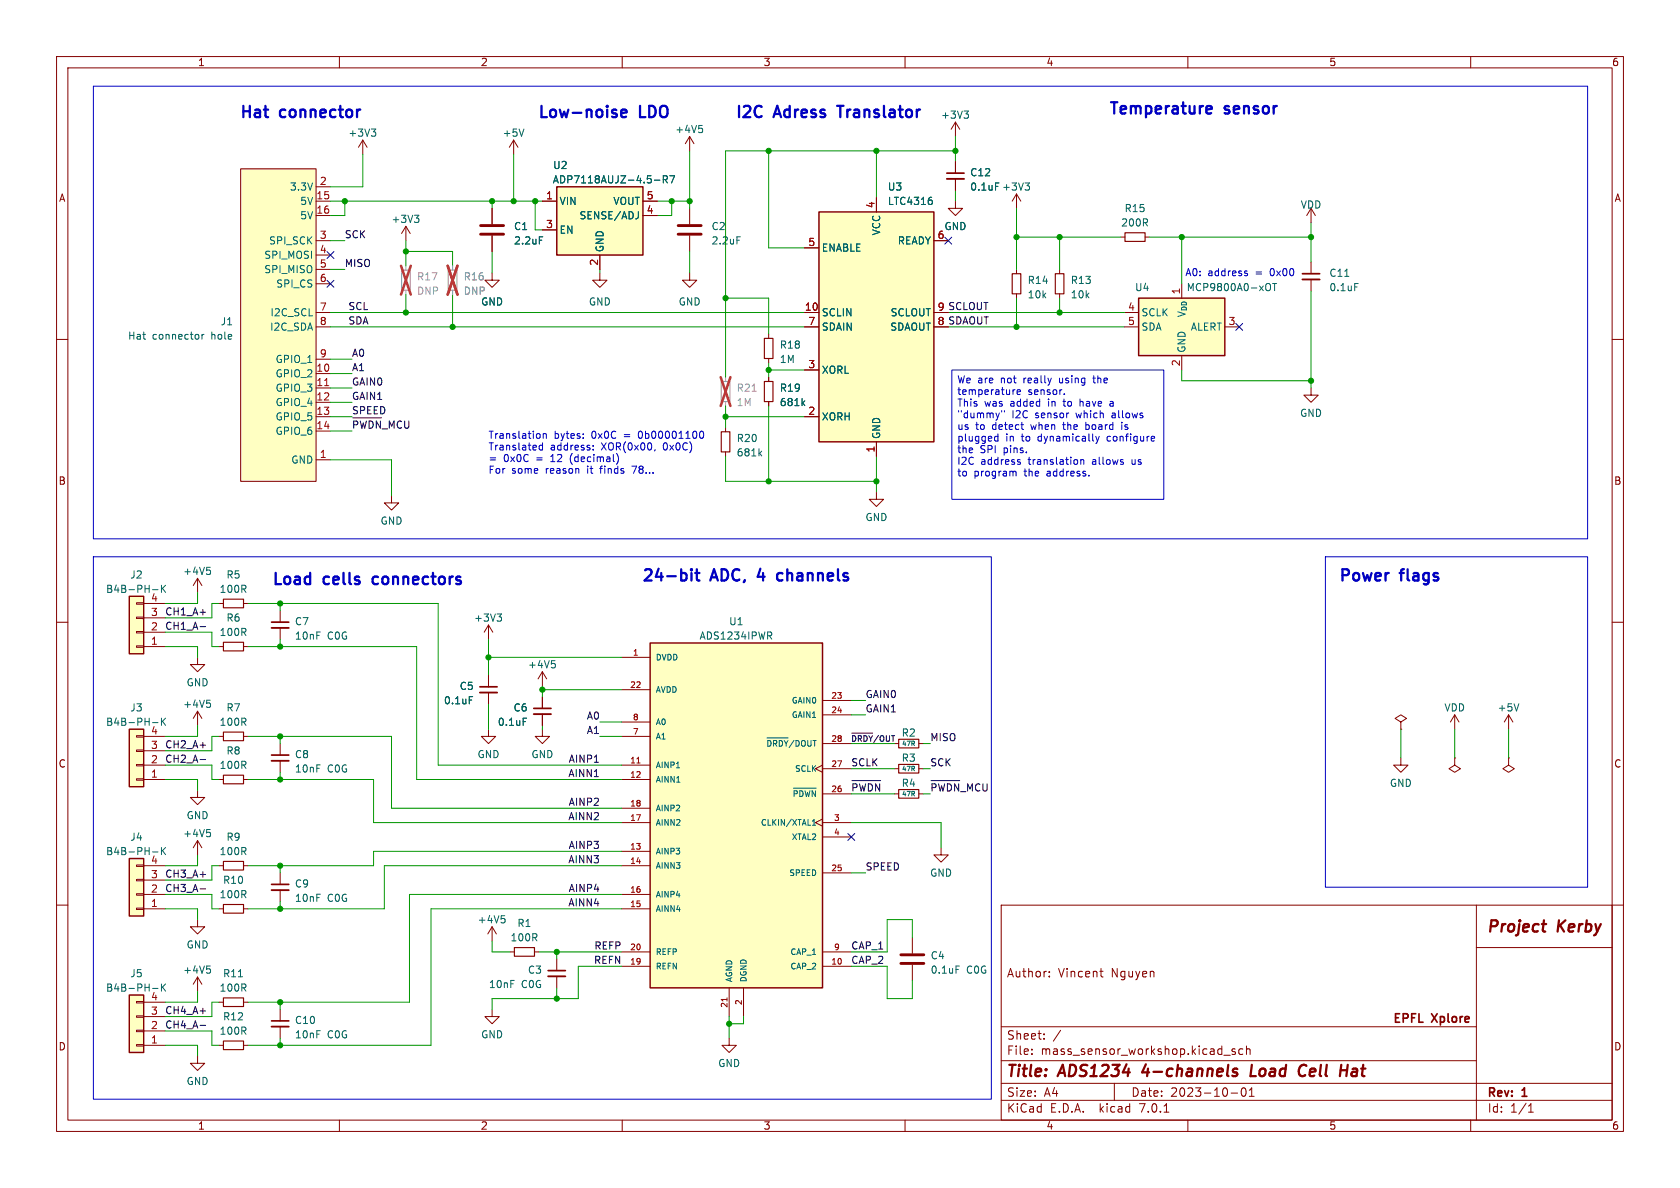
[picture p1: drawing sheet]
<svg xmlns="http://www.w3.org/2000/svg" width="297mm" height="210mm" viewBox="0 0 297 210" stroke-linecap="round" stroke-linejoin="round" font-family="sans-serif">
<defs><g id="words">
<g font-size="2.8" fill="#0000c2">
<text x="42.5" y="21">Hat</text>
<text x="49.7" y="21">connector</text>
<text x="95.2" y="21">Low-noise</text>
<text x="113.3" y="21">LDO</text>
<text x="130.2" y="21">I2C</text>
<text x="137.2" y="21">Adress</text>
<text x="149" y="21">Translator</text>
<text x="196.2" y="20.3">Temperature</text>
<text x="216.7" y="20.3">sensor</text>
<text x="48.3" y="103.5">Load</text>
<text x="57.4" y="103.5">cells</text>
<text x="66.7" y="103.5">connectors</text>
<text x="113.7" y="102.9">24-bit</text>
<text x="126" y="102.9">ADC,</text>
<text x="134.8" y="102.9">4</text>
<text x="138.8" y="102.9">channels</text>
<text x="236.9" y="102.9">Power</text>
<text x="247.8" y="102.9">flags</text>
</g>
<g font-size="2.8" fill="#840000">
<text x="262.7" y="165.3">Project</text>
<text x="275.2" y="165.3">Kerby</text>
<text x="178" y="190.8">Title:</text>
<text x="187.4" y="190.8">ADS1234</text>
<text x="202.7" y="190.8">4-channels</text>
<text x="222.4" y="190.8">Load</text>
<text x="231.5" y="190.8">Cell</text>
<text x="239.4" y="190.8">Hat</text>
</g>
<g font-size="2.1" fill="#840000">
<text x="178" y="172.9">Author:</text>
<text x="187.1" y="172.9">Vincent</text>
<text x="196.4" y="172.9">Nguyen</text>
<text x="178" y="183.9">Sheet:</text>
<text x="186.2" y="183.9">/</text>
<text x="245.9" y="181.1">EPFL</text>
<text x="252.9" y="181.1">Xplore</text>
<text x="178" y="186.6">File:</text>
<text x="184" y="186.6">mass_sensor_workshop.kicad_sch</text>
<text x="178" y="196.8">KiCad</text>
<text x="178" y="194">Size:</text>
<text x="184.6" y="194">A4</text>
<text x="185.7" y="196.8">E.D.A.</text>
<text x="194.4" y="196.8">kicad</text>
<text x="200" y="194">Date:</text>
<text x="201.5" y="196.8">7.0.1</text>
<text x="206.9" y="194">2023-10-01</text>
<text x="263" y="194.2">Rev:</text>
<text x="263" y="196.8">Id:</text>
<text x="267" y="196.8">1/1</text>
<text x="269.2" y="194.2">1</text>
</g>
<g font-size="1.8" fill="#840000">
<text x="35" y="11.8">1</text>
<text x="85" y="11.8">2</text>
<text x="135" y="11.8">3</text>
<text x="185" y="11.8">4</text>
<text x="235" y="11.8">5</text>
<text x="285" y="11.8">6</text>
<text x="10.4" y="35.8">A</text>
<text x="285.4" y="35.8">A</text>
<text x="10.3" y="85.8">B</text>
<text x="285.3" y="85.8">B</text>
<text x="10.3" y="135.8">C</text>
<text x="285.3" y="135.8">C</text>
<text x="10.3" y="185.8">D</text>
<text x="285.3" y="185.8">D</text>
<text x="35" y="199.8">1</text>
<text x="85" y="199.8">2</text>
<text x="135" y="199.8">3</text>
<text x="185" y="199.8">4</text>
<text x="235" y="199.8">5</text>
<text x="285" y="199.8">6</text>
</g>
<g font-size="1.8" fill="#006464">
<text x="119.3" y="23.7">+4V5</text>
<text x="166.3" y="21.1">+3V3</text>
<text x="61.5" y="24.3">+3V3</text>
<text x="88.8" y="24.3">+5V</text>
<text x="51.1" y="33.8">3.3V</text>
<text x="97.7" y="32.6">ADP7118AUJZ-4.5-R7</text>
<text x="97.7" y="30">U2</text>
<text x="156.9" y="33.8">U3</text>
<text x="171.5" y="31.3">C12</text>
<text x="171.5" y="33.9">0.1uF +3V3</text>
<text x="171.5" y="33.9">0.1uF</text>
<text x="52.9" y="36.4">5V</text>
<text x="52.9" y="38.9">5V</text>
<text x="69.2" y="39.6">+3V3</text>
<text x="90.8" y="40.8">C1</text>
<text x="98.9" y="36.4">VIN</text>
<text x="98.9" y="41.5">EN</text>
<text x="102.3" y="38.9">SENSE/ADJ</text>
<text x="108.3" y="36.4">VOUT</text>
<text x="125.7" y="40.8">C2</text>
<text x="155.8" y="41.7" transform="rotate(-90 155.8 41.7)">VCC</text>
<text x="156.9" y="36.4">LTC4316</text>
<text x="166.9" y="40.8">GND</text>
<text x="198.1" y="40.2">200R</text>
<text x="198.8" y="37.7">R15</text>
<text x="229.9" y="37">VDD</text>
<text x="46.6" y="45.9">SPI_MOSI</text>
<text x="47.4" y="43.4">SPI_SCK</text>
<text x="90.8" y="43.4">2.2uF</text>
<text x="106.9" y="44.6" transform="rotate(-90 106.9 44.6)">GND</text>
<text x="125.7" y="43.4">2.2uF</text>
<text x="145.3" y="44.6">ENABLE</text>
<text x="158.6" y="43.4">READY</text>
<text x="46.6" y="48.5">SPI_MISO</text>
<text x="48.7" y="51">SPI_CS</text>
<text x="181.6" y="50.4">R14</text>
<text x="181.6" y="52.9">10k</text>
<text x="189.2" y="50.4">R13</text>
<text x="189.2" y="52.9">10k</text>
<text x="200.6" y="51.6">U4</text>
<text x="209.7" y="51.6">MCP9800A0-xOT</text>
<text x="235" y="49.1">C11</text>
<text x="235" y="51.6">0.1uF</text>
<text x="39" y="57.7">J1</text>
<text x="47.6" y="58.6">I2C_SDA</text>
<text x="47.7" y="56.1">I2C_SCL</text>
<text x="85" y="54.2">GND</text>
<text x="104" y="54.2">GND</text>
<text x="119.9" y="54.2">GND</text>
<text x="145.3" y="56.1">SCLIN</text>
<text x="145.3" y="58.6">SDAIN</text>
<text x="157.3" y="58.6">SDAOUT</text>
<text x="157.3" y="56.1">SCLOUT</text>
<text x="201.8" y="56.1">SCLK</text>
<text x="201.8" y="58.6">SDA</text>
<text x="209.7" y="56.3" transform="rotate(-90 209.7 56.3)">V_{DD}</text>
<text x="210.4" y="58.6">ALERT</text>
<text x="22.6" y="60.2">Hat</text>
<text x="26.9" y="60.2">connector</text>
<text x="37.3" y="60.2">hole</text>
<text x="48.6" y="64.3">GPIO_1</text>
<text x="137.8" y="61.8">R18</text>
<text x="137.8" y="64.3">1M</text>
<text x="209.7" y="62.4" transform="rotate(-90 209.7 62.4)">GND</text>
<text x="48.6" y="66.9">GPIO_2</text>
<text x="48.6" y="69.4">GPIO_3</text>
<text x="48.6" y="71.9">GPIO_4</text>
<text x="137.8" y="69.4">R19</text>
<text x="137.8" y="71.9">681k</text>
<text x="145.3" y="66.2">XORL</text>
<text x="48.6" y="74.5">GPIO_5</text>
<text x="48.6" y="77">GPIO_6</text>
<text x="145.3" y="74.5">XORH</text>
<text x="155.8" y="77.6" transform="rotate(-90 155.8 77.6)">GND</text>
<text x="229.8" y="73.9">GND</text>
<text x="51.4" y="82.1">GND</text>
<text x="130.2" y="78.3">R20</text>
<text x="130.2" y="80.8">681k</text>
<text x="67.2" y="92.9">GND</text>
<text x="152.9" y="92.3">GND</text>
<text x="32.3" y="101.8">+4V5</text>
<text x="18.7" y="105">B4B-PH-K</text>
<text x="23" y="102.4">J2</text>
<text x="38.8" y="105">100R</text>
<text x="40" y="102.4">R5</text>
<text x="38.8" y="112.6">100R</text>
<text x="40" y="110">R6</text>
<text x="52.1" y="110.7">C7</text>
<text x="52.1" y="113.2">10nF</text>
<text x="57.8" y="113.2">C0G</text>
<text x="83.8" y="110">+3V3</text>
<text x="123.6" y="113.2">ADS1234IPWR</text>
<text x="128.8" y="110.7">U1</text>
<text x="93.3" y="118.3">+4V5</text>
<text x="23" y="125.9">J3</text>
<text x="32.3" y="125.3">+4V5</text>
<text x="32.9" y="121.5">GND</text>
<text x="40" y="125.9">R7</text>
<text x="78.4" y="124.7">0.1uF</text>
<text x="81.2" y="122.1">C5</text>
<text x="90.7" y="125.9">C6</text>
<text x="255.3" y="125.9">VDD</text>
<text x="264.7" y="125.9">+5V</text>
<text x="18.7" y="128.5">B4B-PH-K</text>
<text x="38.8" y="128.5">100R</text>
<text x="87.9" y="128.5">0.1uF</text>
<text x="159.4" y="130.4">R2</text>
<text x="38.8" y="136.1">100R</text>
<text x="40" y="133.5">R8</text>
<text x="52.1" y="134.2">C8</text>
<text x="52.1" y="136.7">10nF</text>
<text x="57.8" y="136.7">C0G</text>
<text x="84.4" y="134.2">GND</text>
<text x="93.9" y="134.2">GND</text>
<text x="159.4" y="134.8">R3</text>
<text x="159.4" y="139.3">R4</text>
<text x="245.7" y="139.3">GND</text>
<text x="23" y="148.8">J4</text>
<text x="32.3" y="148.1">+4V5</text>
<text x="32.9" y="145">GND</text>
<text x="40" y="148.8">R9</text>
<text x="18.7" y="151.3">B4B-PH-K</text>
<text x="38.8" y="151.3">100R</text>
<text x="164.4" y="155.1">GND</text>
<text x="38.8" y="158.9">100R</text>
<text x="39.4" y="156.4">R10</text>
<text x="52.1" y="157">C9</text>
<text x="52.1" y="159.6">10nF</text>
<text x="57.8" y="159.6">C0G</text>
<text x="32.9" y="167.8">GND</text>
<text x="84.4" y="163.4">+4V5</text>
<text x="90.2" y="166.6">100R</text>
<text x="91.4" y="164">R1</text>
<text x="23" y="172.9">J5</text>
<text x="32.3" y="172.3">+4V5</text>
<text x="39.4" y="172.9">R11</text>
<text x="93.3" y="172.3">C3</text>
<text x="164.5" y="169.7">C4</text>
<text x="164.5" y="172.3">0.1uF</text>
<text x="170.8" y="172.3">C0G</text>
<text x="18.7" y="175.5">B4B-PH-K</text>
<text x="38.8" y="175.5">100R</text>
<text x="86.4" y="174.8">10nF</text>
<text x="92.1" y="174.8">C0G</text>
<text x="38.8" y="183.1">100R</text>
<text x="39.4" y="180.5">R12</text>
<text x="52.1" y="181.2">C10</text>
<text x="52.1" y="183.7">10nF</text>
<text x="57.8" y="183.7">C0G</text>
<text x="85" y="183.7">GND</text>
<text x="32.9" y="192">GND</text>
<text x="126.9" y="188.8">GND</text>
</g>
<g font-size="1.8" fill="#a90000">
<text x="55.9" y="35.3">15</text>
<text x="56.5" y="32.8">2</text>
<text x="96.5" y="35.3">1</text>
<text x="114.3" y="35.3">5</text>
<text x="55.9" y="37.8">16</text>
<text x="96.5" y="40.4">3</text>
<text x="114.3" y="37.8">4</text>
<text x="154.7" y="36.9" transform="rotate(-90 154.7 36.9)">4</text>
<text x="56.5" y="42.3">3</text>
<text x="56.5" y="44.8">4</text>
<text x="56.5" y="47.4">5</text>
<text x="105.8" y="47" transform="rotate(-90 105.8 47)">2</text>
<text x="142.8" y="43.6">5</text>
<text x="165.7" y="42.3">6</text>
<text x="56.5" y="49.9">6</text>
<text x="208.7" y="52.1" transform="rotate(-90 208.7 52.1)">1</text>
<text x="56.5" y="55">7</text>
<text x="56.5" y="57.5">8</text>
<text x="142.2" y="55">10</text>
<text x="142.8" y="57.5">7</text>
<text x="165.7" y="57.5">8</text>
<text x="165.7" y="55">9</text>
<text x="199.4" y="55">4</text>
<text x="199.4" y="57.5">5</text>
<text x="217.1" y="57.5">3</text>
<text x="55.9" y="65.8">10</text>
<text x="56.5" y="63.2">9</text>
<text x="142.8" y="65.2">3</text>
<text x="208.7" y="64.8" transform="rotate(-90 208.7 64.8)">2</text>
<text x="55.9" y="68.3">11</text>
<text x="55.9" y="70.9">12</text>
<text x="55.9" y="73.4">13</text>
<text x="55.9" y="75.9">14</text>
<text x="142.8" y="73.4">2</text>
<text x="56.5" y="81">1</text>
<text x="154.7" y="80" transform="rotate(-90 154.7 80)">1</text>
<text x="26.6" y="106.4">4</text>
<text x="26.6" y="111.5">2</text>
<text x="26.6" y="109">3</text>
<text x="26.6" y="114">1</text>
<text x="26.6" y="129.9">4</text>
<text x="26.6" y="137.5">1</text>
<text x="26.6" y="135">2</text>
<text x="26.6" y="132.5">3</text>
<text x="26.6" y="155.3">3</text>
<text x="26.6" y="152.8">4</text>
<text x="26.6" y="160.4">1</text>
<text x="26.6" y="157.9">2</text>
<text x="26.6" y="179.5">3</text>
<text x="26.6" y="176.9">4</text>
<text x="26.6" y="184.5">1</text>
<text x="26.6" y="182">2</text>
</g>
<g font-size="1.8" fill="#0f0f0f">
<text x="61" y="42.2">SCK</text>
<text x="61" y="47.3">MISO</text>
<text x="61.6" y="54.9">SCL</text>
<text x="61.6" y="57.4">SDA</text>
<text x="165.7" y="57.5">8 SDAOUT</text>
<text x="165.7" y="55">9 SCLOUT</text>
<text x="62.2" y="65.7">A1</text>
<text x="62.2" y="63.2">A0</text>
<text x="62.2" y="70.8">GAIN1</text>
<text x="62.2" y="68.2">GAIN0</text>
<text x="62.2" y="73.3">SPEED</text>
<text x="62.2" y="75.9">~{PWDN}_MCU</text>
<text x="29.2" y="111.4">CH1_A-</text>
<text x="29.2" y="108.9">CH1_A+</text>
<text x="153" y="123.5">GAIN0</text>
<text x="103.6" y="127.3">A0</text>
<text x="103.6" y="129.8">A1</text>
<text x="153" y="126">GAIN1</text>
<text x="164.5" y="131.1">MISO</text>
<text x="29.2" y="132.4">CH2_A+</text>
<text x="29.2" y="134.9">CH2_A-</text>
<text x="100.4" y="137.4">AINN1</text>
<text x="100.4" y="134.9">AINP1</text>
<text x="150.5" y="135.5">SCLK</text>
<text x="164.5" y="135.5">SCK</text>
<text x="100.4" y="142.5">AINP2</text>
<text x="150.5" y="140">~{PWDN}</text>
<text x="164.5" y="140">~{PWDN}_MCU</text>
<text x="100.4" y="145.1">AINN2</text>
<text x="29.2" y="155.2">CH3_A+</text>
<text x="100.4" y="152.7">AINN3</text>
<text x="100.4" y="150.1">AINP3</text>
<text x="153" y="154">SPEED</text>
<text x="29.2" y="157.8">CH3_A-</text>
<text x="100.4" y="160.3">AINN4</text>
<text x="100.4" y="157.8">AINP4</text>
<text x="105" y="167.9">REFP</text>
<text x="150.5" y="167.9">CAP_1</text>
<text x="104.9" y="170.5">REFN</text>
<text x="150.5" y="170.5">CAP_2</text>
<text x="29.2" y="179.4">CH4_A+</text>
<text x="29.2" y="181.9">CH4_A-</text>
</g>
<g font-size="1.8" fill="#989898">
<text x="73.7" y="49.7">R17</text>
<text x="73.7" y="52.3">DNP</text>
<text x="81.9" y="49.7">R16</text>
<text x="81.9" y="52.3">DNP</text>
<text x="130.2" y="69.4">R21</text>
<text x="130.2" y="71.9">1M</text>
</g>
<g font-size="1.8" fill="#0000c2">
<text x="209.5" y="48.9">A0:</text>
<text x="213.5" y="48.9">address</text>
<text x="222" y="48.9">=</text>
<text x="224.7" y="48.9">0x00</text>
<text x="169.2" y="68">We are</text>
<text x="169.2" y="70.1">temperature</text>
<text x="177" y="68">not</text>
<text x="181.1" y="68">really</text>
<text x="181.8" y="70.1">sensor.</text>
<text x="187.5" y="68">using</text>
<text x="193.7" y="68">the</text>
<text x="86.4" y="77.6">Translation</text>
<text x="98" y="77.6">bytes:</text>
<text x="104.6" y="77.6">0x0C</text>
<text x="110.4" y="77.6">=</text>
<text x="113.1" y="77.6">0b00001100</text>
<text x="169.2" y="72.1">This</text>
<text x="169.2" y="74.2">&quot;dummy&quot;</text>
<text x="169.2" y="76.2">us</text>
<text x="172.5" y="76.2">to</text>
<text x="174.1" y="72.1">was</text>
<text x="175.5" y="76.2">detect</text>
<text x="178.7" y="72.1">added</text>
<text x="178.9" y="74.2">I2C</text>
<text x="182.4" y="76.2">when</text>
<text x="183.1" y="74.2">sensor</text>
<text x="185.5" y="72.1">in</text>
<text x="188.2" y="76.2">the</text>
<text x="188.3" y="72.1">to</text>
<text x="190.4" y="74.2">which</text>
<text x="191.3" y="72.1">have</text>
<text x="192.3" y="76.2">board</text>
<text x="196.7" y="72.1">a</text>
<text x="196.8" y="74.2">allows</text>
<text x="198.8" y="76.2">is</text>
<text x="86.4" y="79.7">Translated</text>
<text x="86.4" y="81.8">=</text>
<text x="86.4" y="83.8">For</text>
<text x="89" y="81.8">0x0C</text>
<text x="90.5" y="83.8">some</text>
<text x="94.8" y="81.8">=</text>
<text x="96.5" y="83.8">reason</text>
<text x="97.3" y="79.7">address:</text>
<text x="97.5" y="81.8">12</text>
<text x="101" y="81.8">(decimal)</text>
<text x="104" y="83.8">it</text>
<text x="106.4" y="79.7">XOR(0x00,</text>
<text x="106.4" y="83.8">finds</text>
<text x="112.2" y="83.8">78...</text>
<text x="117.4" y="79.7">0x0C)</text>
<text x="169.2" y="78.3">plugged</text>
<text x="169.2" y="80.4">the</text>
<text x="169.2" y="82.4">I2C</text>
<text x="173.3" y="80.4">SPI</text>
<text x="173.4" y="82.4">address</text>
<text x="177.5" y="80.4">pins.</text>
<text x="177.8" y="78.3">in</text>
<text x="180.7" y="78.3">to</text>
<text x="181.9" y="82.4">translation</text>
<text x="183.6" y="78.3">dynamically</text>
<text x="193.3" y="82.4">allows</text>
<text x="196" y="78.3">configure</text>
<text x="200.3" y="82.4">us</text>
<text x="169.2" y="84.5">to</text>
<text x="172.2" y="84.5">program</text>
<text x="181.2" y="84.5">the</text>
<text x="185.2" y="84.5">address.</text>
</g>
<g font-size="1.4" fill="#a90000">
<text x="111.8" y="116">1</text>
<text x="111.3" y="121.7">22</text>
<text x="146.9" y="123.6">23</text>
<text x="111.8" y="129.9">7</text>
<text x="111.8" y="127.4">8</text>
<text x="146.9" y="126.1">24</text>
<text x="146.9" y="131.2">28</text>
<text x="111.3" y="135">11</text>
<text x="111.3" y="137.5">12</text>
<text x="146.9" y="135.6">27</text>
<text x="111.3" y="142.6">18</text>
<text x="146.9" y="140.1">26</text>
<text x="111.3" y="145.2">17</text>
<text x="147.4" y="145.2">3</text>
<text x="147.4" y="147.7">4</text>
<text x="111.3" y="150.2">13</text>
<text x="111.3" y="152.8">14</text>
<text x="146.9" y="154.1">25</text>
<text x="111.3" y="160.4">15</text>
<text x="111.3" y="157.9">16</text>
<text x="111.3" y="170.6">19</text>
<text x="111.3" y="168">20</text>
<text x="146.9" y="170.6">10</text>
<text x="147.4" y="168">9</text>
<text x="128.7" y="178.2" transform="rotate(-90 128.7 178.2)">21</text>
<text x="131.2" y="177.7" transform="rotate(-90 131.2 177.7)">2</text>
</g>
<g font-size="1.4" fill="#006464">
<text x="116" y="116.9">DVDD</text>
<text x="116" y="122.6">AVDD</text>
<text x="139.8" y="124.5">GAIN0</text>
<text x="116" y="130.9">A1</text>
<text x="116" y="128.3">A0</text>
<text x="139.8" y="127.1">GAIN1</text>
<text x="116" y="136">AINP1</text>
<text x="135.3" y="132.6">~{DRDY}/DOUT</text>
<text x="140.4" y="136.6">SCLK</text>
<text x="116" y="138.5">AINN1</text>
<text x="116" y="143.6">AINP2</text>
<text x="140" y="141.5">~{PDWN}</text>
<text x="116" y="146.1">AINN2</text>
<text x="134.4" y="146.1">CLKIN/XTAL1</text>
<text x="139.8" y="148.7">XTAL2</text>
<text x="116" y="151.2">AINP3</text>
<text x="116" y="153.7">AINN3</text>
<text x="139.4" y="155">SPEED</text>
<text x="116" y="161.4">AINN4</text>
<text x="116" y="158.8">AINP4</text>
<text x="116" y="171.5">REFN</text>
<text x="116" y="169">REFP</text>
<text x="129.6" y="173.6" transform="rotate(-90 129.6 173.6)">AGND</text>
<text x="132.1" y="173.6" transform="rotate(-90 132.1 173.6)">DGND</text>
<text x="139.6" y="171.5">CAP_2</text>
<text x="139.6" y="169">CAP_1</text>
</g>
<text font-size="1.4" fill="#0f0f0f" x="150.5" y="131.2">~{DRDY}/OUT</text>
<g font-size="1.1" fill="#006464">
<text x="159.4" y="132">47R</text>
<text x="159.4" y="136.5">47R</text>
<text x="159.4" y="140.9">47R</text>
</g>
</g></defs>
<g fill="none" stroke="#840000" stroke-width=".18">
<path d="M10 10h277v190h-277zM12 12h273v186h-273zM60 10v2M110 10v2M160 10v2M210 10v2M260 10v2M42.5 29.8h13.4v55.3h-13.4zM55.9 35.6h2.5M55.9 38.1h2.5M55.9 33h2.5M64.1 24.8l-.7 1.2"/>
<path d="M64.1 24.8v2.5M64.1 24.8l.8 1.2M87 36.8v2.8M90.8 24.8l-.8 1.2M90.8 24.8v2.5M90.8 24.8l.8 1.2M95.9 35.6h2.5M113.7 35.6h2.5M113.7 38.1h2.5M121.9 24.1l-.7 1.3M121.9 24.1v2.6M121.9 36.8v2.8"/>
<path d="M121.9 24.1l.8 1.3M154.9 34.9v2.6M168.9 35.6v1.2h1.3l-1.3 1.3-1.3-1.3h1.3M168.9 21.6l-.8 1.3M168.9 21.6v2.5M168.9 28.6v2M168.9 31.6v2.1M168.9 21.6l.8 1.3M179.7 34.3v2.5M179.7 34.3l-.8 1.3M179.7 34.3l.8 1.3M231.8 36.8v2.6"/>
<path d="M231.8 36.8l-.8 1.3M231.8 36.8l.7 1.3M10 60h2M55.9 42.5h2.5M55.9 45.1h2.5M55.9 47.6h2.5M55.9 50.2h2.5M55.9 55.2h2.5M55.9 57.8h2.5M71.8 40l-.8 1.3M71.8 40v2.5M71.8 40l.7 1.3"/>
<path d="M87 48.3v1.2h1.3l-1.3 1.3-1.3-1.3h1.3M87 41.7v2.8M95.9 40.6h2.5M106 48.3v1.2h1.3l-1.3 1.3-1.2-1.3h1.2M106 45.1v2.5M121.9 48.3v1.2h1.3l-1.3 1.3-1.3-1.3h1.3M121.9 41.7v2.8M135.9 59.1v.7M142.2 55.2h2.6M142.2 57.8h2.6M142.2 43.8h2.6M165.1 42.5h2.5"/>
<path d="M165.1 55.2h2.5M165.1 57.8h2.5M179.7 47.6v.8M179.7 51.9v.8M187.3 47.6v.8M187.3 51.9v.8M198.1 41.9h.8M198.8 55.2h2.5M198.8 57.8h2.5M202.4 41.9h.8M216.5 57.8h2.6M231.8 46.4v2"/>
<path d="M231.8 49.4v2M285 60h2M55.9 66h2.5M55.9 68.6h2.5M55.9 71.1h2.5M55.9 73.7h2.5M55.9 76.2h2.5M55.9 63.5h2.5M128.3 75.6v.7M128.3 79.9v.7M135.9 63.4v.7M135.9 66.7v.7"/>
<path d="M135.9 71v.8M142.2 73.7h2.6M142.2 65.4h2.6M154.9 78.1v2.5M208.9 62.9v2.5M231.8 68.6v1.3h1.2l-1.2 1.2-1.3-1.2h1.3M55.9 81.3h2.5M69.2 87.6v1.3h1.3l-1.3 1.3-1.3-1.3h1.3M154.9 87v1.3h1.3l-1.3 1.2-1.2-1.2h1.2M10 110h2M24.1 106.6h1.3v.2h-1.3zM24.1 109.1h1.3v.2h-1.3z"/>
<path d="M24.1 111.6h1.3v.3h-1.3zM24.1 114.2h1.3v.2h-1.3zM25.4 106.7h3.8M25.4 114.3h3.8M25.4 111.8h3.8M25.4 109.2h3.8M34.9 116.2v1.3h1.3l-1.3 1.2-1.2-1.2h1.2M34.9 102.2v2.6M34.9 102.2l-.7 1.3M34.9 102.2l.8 1.3M38.7 106.7h.8M38.7 114.3h.8"/>
<path d="M43.1 106.7h.7M43.1 114.3h.7M49.5 108v2M49.5 111v2M86.4 110.5v2.5M86.4 119.4v2M86.4 110.5l-.8 1.3M86.4 110.5l.7 1.3M95.9 118.7v2.6M95.9 118.7l-.8 1.3M95.9 118.7l.7 1.3M109.9 116.2h5"/>
<path d="M285 110h2M24.1 130h1.3v.3h-1.3zM24.1 132.6h1.3v.2h-1.3zM24.1 135.1h1.3v.3h-1.3zM24.1 137.7h1.3v.2h-1.3zM25.4 137.8h3.8M25.4 135.3h3.8M25.4 132.7h3.8M25.4 130.2h3.8M34.9 139.7v1.3h1.3l-1.3 1.2-1.2-1.2h1.2M34.9 125.7v2.6M34.9 125.7l-.7 1.3"/>
<path d="M34.9 125.7l.8 1.3M38.7 137.8h.8M38.7 130.2h.8M43.1 137.8h.7M43.1 130.2h.7M49.5 131.4v2.1M49.5 134.5v2M86.4 128.9v1.3h1.2l-1.2 1.2-1.3-1.2h1.3M86.4 122.4v2.1M95.9 128.9v1.3h1.3l-1.3 1.2-1.3-1.2h1.3M95.9 123.2v2M95.9 126.2v2.1"/>
<path d="M109.9 137.8h5M109.9 135.3h5M109.9 130.2h5M109.9 121.9h5M109.9 127.6h5M145.4 135.3l-1.3 .6 1.3 .6M145.4 131.4h5.1M145.4 135.9h5.1M145.4 123.8h5.1M145.4 126.4h5.1M158.1 135.9h.8M162.4 131.4h.8"/>
<path d="M162.4 135.9h.8M247.6 127.6l1.1-.6-1.1-.6-1 .6 1 .6v1.3M247.6 128.9h.1M247.6 134v1.3h1.3l-1.3 1.2-1.2-1.2h1.2M257.2 134v1.3l1 .6-1 .6-1-.6 1-.6M257.2 134h.1M257.2 126.4l-.8 1.2M257.2 126.4v2.5M257.2 126.4l.7 1.2M266.7 134v1.3l1 .6-1 .6-1-.6 1-.6M266.7 134h.1M266.7 126.4l-.8 1.2"/>
<path d="M266.7 126.4v2.5M266.7 126.4l.8 1.2M10 160h2M24.1 152.9h1.3v.3h-1.3zM24.1 155.4h1.3v.3h-1.3zM24.1 158h1.3v.2h-1.3zM25.4 158.1h3.8M25.4 155.6h3.8M25.4 153h3.8M34.9 148.6v2.5M34.9 148.6l-.7 1.3M34.9 148.6l.8 1.3"/>
<path d="M38.7 153h.8M43.1 153h.7M49.5 154.3v2M49.5 157.4v2M109.9 158.1h5M109.9 153h5M109.9 150.5h5M109.9 145.4h5M109.9 142.9h5M145.4 144.8l-1.3 .6 1.3 .7M145.4 140.3h5.1M145.4 145.4h5.1"/>
<path d="M145.4 154.3h5.1M145.4 148h5.1M158.1 140.3h.8M162.4 140.3h.8M166.4 149.9v1.2h1.2l-1.2 1.3-1.3-1.3h1.3M285 160h2M24.1 160.5h1.3v.3h-1.3zM24.1 177h1.3v.3h-1.3zM24.1 179.6h1.3v.2h-1.3zM25.4 177.2h3.8M25.4 160.7h3.8M25.4 179.7h3.8"/>
<path d="M34.9 162.6v1.2h1.3l-1.3 1.3-1.2-1.3h1.2M34.9 172.7l-.7 1.3M34.9 172.7v2.6M34.9 172.7l.8 1.3M38.7 177.2h.8M38.7 160.7h.8M43.1 177.2h.7M43.1 160.7h.7M49.5 178.4v2.1M87 178.4v1.3h1.3l-1.3 1.3-1.3-1.3h1.3M87 163.8l-.8 1.3M87 163.8v2.6"/>
<path d="M87 163.8l.8 1.3M90.2 168.3h.7M94.5 168.3h.7M98.4 169.5v2.1M98.4 172.6v2M109.9 160.7h5M109.9 168.3h5M109.9 170.8h5M128.9 174.6v5.1M131.4 174.6v5.1M145.4 168.3h5.1M145.4 170.8h5.1"/>
<path d="M161.3 165.7v2.8M161.3 170.6v2.8M177 160h108v38h-108zM185.5 172.6v.1M185.5 171.8v.1M194.4 171.7h.6M194.7 172.6l.3 .1M261 160v38M261 167.5h24M24.1 182.1h1.3v.3h-1.3zM24.1 184.7h1.3v.2h-1.3zM25.4 184.8h3.8"/>
<path d="M25.4 182.2h3.8M34.9 186.7v1.3h1.3l-1.3 1.2-1.2-1.2h1.2M38.7 184.8h.8M43.1 184.8h.7M49.5 181.5v2M60 198v2M110 198v2M128.9 183.5v1.3h1.3l-1.3 1.3-1.3-1.3h1.3M160 198v2M177 194.5h108M177 191.5h108M177 187.5h84"/>
<path d="M177 181.5h84M182.4 186.3v.1M182.4 185.5v.1M184.6 183.6v.1M184.6 182.8v.1M197 191.5v3M205.8 196.6h.8M210 198v2M216.4 186.5h1.1M217.6 193.2h1.2M218.4 185.5l-.4-.1-.2 .2 .1 .2 .5 .2v.3h-.6M219.6 192.4l.2-.1a.81 .81 0 0 1 .6 .6 .81 .81 0 0 1-.3 .8l-.2 .1a.81 .81 0 0 1-.6-.6 .81 .81 0 0 1 .3-.8z"/>
<path d="M219.7 185.5l-.4-.1-.3 .3v.4l.1 .2h.6M220.4 185.5l.2-.1 .3 .1 .1 .9M220.4 184.9v1.5M220.9 193.8h.8M220.9 192.7l.4-.4v1.5M260 198v2M270.2 196.6h.9M270.2 195.5l.4-.4v1.5"/>
</g>
<path d="M272.6 163.3h.7M218.1 189l.2-.1 .5 .1M218.2 189.6l.5 .1v.2l-.3 .3h-.4M221.3 188.2l-.2 2h.9M230.1 188.3l.3-.1 .5 .1M230.8 190l-.6 .2M237 189.2h1.1M238.3 188.2l-.3 2" fill="none" stroke="#840000" stroke-width=".4"/>
<g fill="none" stroke="#840000" stroke-width=".2">
<path d="M135.1 59.8h1.6v3.6h-1.6zM178.9 48.4h1.6v3.5h-1.6zM186.6 48.4h1.5v3.5h-1.5zM198.9 41.1h3.5v1.6h-3.5zM127.5 76.3h1.5v3.6h-1.5zM135.1 67.4h1.6v3.6h-1.6zM39.5 105.9h3.6v1.5h-3.6zM39.5 113.5h3.6v1.6h-3.6zM39.5 129.4h3.6v1.5h-3.6zM39.5 137h3.6v1.6h-3.6zM158.9 130.7h3.5v1.5h-3.5zM158.9 139.6h3.5v1.5h-3.5z"/>
<path d="M158.9 135.1h3.5v1.6h-3.5zM39.5 159.9h3.6v1.5h-3.6zM39.5 152.3h3.6v1.5h-3.6zM39.5 176.4h3.6v1.5h-3.6zM90.9 167.5h3.6v1.5h-3.6zM39.5 184h3.6v1.5h-3.6z"/>
</g>
<g fill="#ffffc2" stroke="#ffffc2" stroke-width=".18">
<path d="M42.5 29.8h13.4v55.3h-13.4z"/>
<path d="M144.8 37.5h20.3v40.6h-20.3z"/>
<path d="M22.9 151.8h2.5v10.1h-2.5z"/>
<path d="M22.9 128.9h2.5v10.2h-2.5z"/>
<path d="M22.9 105.4h2.5v10.2h-2.5z"/>
<path d="M201.3 52.7h15.2v10.2h-15.2z"/>
<path d="M22.9 175.9h2.5v10.2h-2.5z"/>
<path d="M114.9 113.7h30.5v60.9h-30.5z"/>
<path d="M98.4 33h15.3v12.1h-15.3z"/>
</g>
<path d="M57.4 68.2h.7M112.6 134.9h.6M128.5 176.4v.6" fill="none" stroke="#a90000" stroke-width=".18"/>
<g fill="none" stroke="#006464" stroke-width=".18">
<path d="M170.4 19.6h.8l-.4 .5M65.6 22.8h.8l-.4 .5M66.2 23.3l.2 .2v.3l-.2 .3M73.3 38.1h.8l-.5 .4M73.8 38.5l.3 .3v.3l-.3 .2M92.6 22.8l-.4 1.3M112.9 37.4v.9l-.4 .4M115.7 31.9h1M117.3 31.7h.6l.1-.2-.1-.3-.6-.1v1.2M117.6 31.7l.4 .6M118.4 31.1h.9l-.6 1.2M123.6 22.2h.6"/>
<path d="M124 22.7l.2 .2v.3l-.2 .2M164.7 35.4l.1 .2-.1 .5M171 20.1l.2 .3v.3l-.2 .2M181.2 32.3h.8l-.4 .5M181.8 32.8l.2 .3v.3l-.2 .2M35.7 59.1v.9M36.1 59.1l-.4 .3M95.4 41.9h.6M130.3 41.9h.6M224.1 50.1a.43 .43 0 0 1 .5 .4v.5a.43 .43 0 0 1-.5 .4M225 50.1h.7M225.3 50.1v1.3"/>
<path d="M239.5 50.1h.6M134.7 79.8l-.5 .4M141.9 71.2l.4 .5M142.3 70.9l-.5 .4M134.3 80.1l.4 .5M27 104.2h.9M28.5 103.5v1.2M28.7 104l.6 .7M29.3 103.5l-.8 .7M36.6 100.3h.6M37 100.8l.2 .2v.3l-.2 .3M87.9 108.5h.8l-.5 .5"/>
<path d="M88.4 109l.3 .3v.3l-.3 .2M97.5 116.8h.6M97.9 117.3l.3 .2v.3l-.3 .3M136 112.4l.4 .6M136.3 111.8l.1 .2-.1 .3M27 127.7h.9M28.5 127v1.2M28.7 127.5l.6 .7M29.3 127l-.8 .7M36.6 123.8h.6M37 124.3l.2 .2v.3l-.2 .2M83 123.1h.6"/>
<path d="M92.5 127h.6M135.6 130.4h3.7M136.3 131.1l-.2-.2h-.4v1M137.3 131.2l-.1-.3h-.4v1M138.3 131.1l-.1-.2h-.4v1M138.6 130.9l.4 .5 .3-.5M140.2 139.3h4.1M140.4 130.9l-.9 1.3M141.3 131.1l-.2-.2h-.4v1M141.7 131.2a.34 .34 0 0 1 .3-.3 .34 .34 0 0 1 .4 .3M142.3 139.8l.3 1M142.8 130.9v.8"/>
<path d="M143.2 139.8l-.3 1M143.4 130.9v.8M143.7 130.9h.6M144 130.9v1M144.2 139.8v1l-.6-1v1M268.5 124.4l-.4 1.3M27 150.6h.9M28.5 149.8v1.3M28.7 150.4l.6 .7M29.3 149.8l-.8 .7M36.6 146.6h.6M37 147.1l.2 .3v.3l-.2 .2"/>
<path d="M141 140.1l-.1-.3h-.5v1M141.9 140l-.1-.2h-.4v1M143.6 145.9h.6M143.6 145.2l.3-.3v1M27 174.7h.9M28.5 173.9v1.3M28.7 174.5l.6 .7M29.3 173.9l-.8 .8M36.6 170.8h.6M37 171.3l.2 .2v.3l-.2 .2M88.6 161.9h.6M89.1 162.4l.2 .2v.3l-.2 .2"/>
<path d="M169 170.8h.6"/>
</g>
<path d="M85 39.9h4M119.9 39.9h4.1M85 41.4h4M119.9 41.4h4.1M159.3 170.3h4M159.3 168.8h4" fill="none" stroke="#840000" stroke-width=".51"/>
<path d="M167.4 31.6h3M230.3 49.4h3M48 111h3.1M48 134.5h3.1M84.8 122.4h3.1M94.4 126.2h3M48 157.4h3.1M96.9 172.6h3M48 181.5h3.1" fill="none" stroke="#840000" stroke-width=".33"/>
<path d="M167.4 30.6h3M230.3 48.4h3M48 110h3.1M48 133.5h3.1M84.8 121.4h3.1M94.4 125.2h3M48 156.3h3.1M96.9 171.6h3M48 180.5h3.1" fill="none" stroke="#840000" stroke-width=".3"/>
<path d="M98.4 33h15.3v12.1h-15.3zM144.8 37.5h20.3v40.6h-20.3zM201.3 52.7h15.2v10.2h-15.2zM22.9 105.4h2.5v10.2h-2.5zM114.9 113.7h30.5v60.9h-30.5zM22.9 128.9h2.5v10.2h-2.5zM22.9 151.8h2.5v10.1h-2.5zM22.9 175.9h2.5v10.2h-2.5z" fill="none" stroke="#840000" stroke-width=".25"/>
<path d="M71 47.8h1.5v3.5h-1.5zM79.2 47.8h1.6v3.5h-1.6zM127.5 67.4h1.5v3.6h-1.5z" fill="none" stroke="#a1a1a1" stroke-width=".2"/>
<path d="M71.8 47v.8M71.8 51.3v.8M80 47v.8M80 51.3v.8M128.3 66.7v.7M128.3 71v.8" fill="none" stroke="#a1a1a1" stroke-width=".18"/>
<path d="M70.9 47l1.7 5.1M72.6 47l-1.7 5.1M79.1 47l1.8 5.1M80.9 47l-1.8 5.1M127.4 66.7l1.7 5.1M129.1 66.7l-1.7 5.1" fill="none" stroke="#eb3a3d" stroke-width=".46"/>
<path d="M62.4 73.9h5M35.4 110.8h.9M35.4 134.3h.9M105.1 134.8h.7M150.6 129.6h3.7M150.6 138h5.1M164.6 138h5.1M35.4 157.1h.9M35.4 181.3h.9" fill="none" stroke="#0f0f0f" stroke-width=".18"/>
<path d="M109.9 19.5l.6-.1 .2 .1 .1 .4-1 .1M148 18.7h1.1M213.9 18.7l.2 .1 .1 .4-.9 .2M214.1 20l-.2 .1M109.9 20.6l.2 .1 .6-.1M122.2 100.6v.2M122.2 101.3v1.3M122.2 100.6l-.1 .1 .1 .1M122.2 100.6l.1 .1-.1 .1M122.9 101.3h.8M123.2 100.6v1.7l.1 .2 .4 .1M138.1 101.3l-.5 .1-.2 .3 .1 .7 .3 .2h.3" fill="none" stroke="#0000c2" stroke-width=".4"/>
<g fill="none" stroke="#0000c2" stroke-width=".18">
<path d="M16.5 15.2h264.2v80.1h-264.2zM220.4 48.3l.2 .2-.2 .2M220.4 47.9l.1 .1M95.9 78.3v1.2M95.9 78.8l-.3-.1-.3 .2 .1 .6h.5M96 76.6v.9M96 76.8l.2-.2 .3 .1 .1 .8M103.1 77.4v.1M103.1 76.7v.1M104.9 79.4v.1M104.9 78.8v.1M115.8 79.5l-.1 .2"/>
<path d="M123.8 76.3l.2-.1a.68 .68 0 0 1 .4 .7 .68 .68 0 0 1-.4 .6l-.2-.1-.1-.4zM168.3 65.4h37.4v22.9h-37.4zM175.9 77.9h.5M175.9 77.2h.5M176.4 76.7v1.3M177.1 72.6v.2M177.6 72.6v.2M179.4 68.9l-.2 .1M179.8 69.3l.6-.1v-.2l-.4-.1-.2 .2 .1 .6h.5M180.5 75.1h.5M180.8 75.9h.2M188.2 69.6v.1"/>
<path d="M193.7 77.1l.3 .9M194 78l-.3 .4M194.3 77.1l-.3 .9M203.7 77.1l.4 .1v.2l-.6 .2M204.1 77.9l-.4 .1M16.5 98.4h158.8v95.9h-158.8zM109.2 80.5l.1 .7-.3 .8M179.3 83.3l.3 .2v.6M180.2 81.7l.2 .1-.2 .3M191.1 81.2v.9M191.1 81.4l.1-.2 .3 .1 .1 .8M192.5 84v.1"/>
<path d="M234.3 98.4h46.4v58.4h-46.4z"/>
</g>
<g fill="none" stroke="#009600" stroke-width=".18">
<path d="M58.4 35.6h37.5M61 35.6v2.5h-2.6M64.1 27.3v5.7h-5.7M87 35.6v1.2M90.8 27.3v8.3M94.6 35.6v5h1.3M116.2 35.6h5.7M118.7 35.6v2.5h-2.5M121.9 26.7v10.1M135.9 26.7v17.1h6.3M154.9 26.7v8.2M168.9 26.7h-40.6v40"/>
<path d="M168.9 24.1v4.5M168.9 33.7v1.9M179.7 36.8v10.8M231.8 39.4v7M58.4 57.8h83.8M58.4 55.2h83.8M58.4 42.5h2.6M58.4 47.6h2.6M71.8 42.5v4.5M71.8 52.1v3.1M71.8 44.5h8.2v2.5M80 52.1v5.7"/>
<path d="M87 44.5v3.8M106 47.6v.7M121.9 44.5v3.8M128.3 52.7h7.6v6.4M167.6 57.8h31.2M167.6 55.2h31.2M179.7 41.9h18.4M179.7 52.7v5.1M187.3 41.9v5.7M187.3 52.7v2.5M203.2 41.9h28.6M208.9 41.9v8.3"/>
<path d="M231.8 51.4v17.2M58.4 73.7h3.8M58.4 68.6h3.8M58.4 63.5h3.8M58.4 66h3.8M58.4 71.1h3.8M58.4 76.2h3.8M128.3 73.7h13.9M128.3 71.8v3.8M135.9 64.1v2.6M135.9 71.8v13.3M135.9 65.4h6.3"/>
<path d="M208.9 65.4v1.9h22.9M58.4 81.3h10.8v6.3M128.3 80.6v4.5h26.6M154.9 80.6v6.4M29.2 114.3h5.7v1.9M29.2 111.8h8.3v2.5h1.2M34.9 104.8v1.9h-5.7M38.7 106.7h-1.2v2.5h-8.3M43.8 114.3h29.9v23.5h36.2M43.8 106.7h33.7v28.6h32.4M49.5 106.7v1.3M49.5 113v1.3"/>
<path d="M86.4 113v6.4M86.4 116.2h23.5M29.2 137.8h5.7v1.9M29.2 135.3h8.3v2.5h1.2M34.9 128.3v1.9h-5.7M38.7 130.2h-1.2v2.5h-8.3M43.8 137.8h22.2v7.6h43.9M43.8 130.2h25.4v12.7h40.7M49.5 130.2v1.2M49.5 136.5v1.3M86.4 124.5v4.4M95.9 121.9h14"/>
<path d="M95.9 121.3v1.9M95.9 128.3v.6M106 130.2h3.9M106 127.6h3.9M150.5 135.9h7.6M150.5 126.4h2.5M150.5 123.8h2.5M150.5 131.4h7.6M163.2 135.9h1.3M163.2 131.4h1.3M247.6 128.9v5.1M257.2 128.9v5.1"/>
<path d="M266.7 128.9v5.1M29.2 158.1h8.3v2.6h1.2M34.9 151.1v1.9h-5.7M38.7 153h-1.2v2.6h-8.3M49.5 153v1.3M49.5 159.4v1.3M109.9 158.1h-37.5v19.1h-28.6M109.9 153h-42v7.7h-24.1M109.9 150.5h-43.9v2.5h-22.2M150.5 154.3h2.5M150.5 145.4h15.9v4.5M150.5 140.3h7.6"/>
<path d="M163.2 140.3h1.3M29.2 160.7h5.7v1.9M34.9 175.3v1.9h-5.7M38.7 177.2h-1.2v2.5h-8.3M49.5 177.2v1.2M87 166.4v1.9h3.2M95.2 168.3h14.7M98.4 168.3v1.2M98.4 174.6v1.9M109.9 170.8h-7.7v5.7h-15.2v1.9M109.9 160.7h-33.7v24.1h-32.4M128.9 179.7v3.8"/>
<path d="M131.4 179.7v1.3h-2.5M150.5 170.8h6.3v5.7h4.5v-3.1M161.3 165.7v-3.1h-4.5v5.7h-6.3M29.2 184.8h5.7v1.9M29.2 182.2h8.3v2.6h1.2M49.5 183.5v1.3"/>
</g>
<path d="M57.8 44.5l1.2 1.2M57.8 49.6l1.2 1.2M59 44.5l-1.2 1.2M59 49.6l-1.2 1.2M167 41.9l1.2 1.3M168.2 41.9l-1.2 1.3M218.5 57.2l1.2 1.2M219.7 57.2l-1.2 1.2M149.9 147.3l1.2 1.3M151.1 147.3l-1.2 1.3" fill="none" stroke="#000084" stroke-width=".18"/>
<g fill="#009600" stroke="#009600" stroke-width=".18">
<circle cx="49.5" cy="184.8" r=".46"/>
<circle cx="49.5" cy="177.2" r=".46"/>
<circle cx="98.4" cy="176.5" r=".46"/>
<circle cx="98.4" cy="168.3" r=".46"/>
<circle cx="49.5" cy="153" r=".46"/>
<circle cx="49.5" cy="160.7" r=".46"/>
<circle cx="49.5" cy="130.2" r=".46"/>
<circle cx="49.5" cy="106.7" r=".46"/>
<circle cx="49.5" cy="114.3" r=".46"/>
<circle cx="49.5" cy="137.8" r=".46"/>
<circle cx="128.9" cy="181" r=".46"/>
<circle cx="86.4" cy="116.2" r=".46"/>
<circle cx="95.9" cy="121.9" r=".46"/>
<circle cx="154.9" cy="26.7" r=".46"/>
<circle cx="168.9" cy="26.7" r=".46"/>
<circle cx="154.9" cy="85.1" r=".46"/>
<circle cx="128.3" cy="73.7" r=".46"/>
<circle cx="135.9" cy="65.4" r=".46"/>
<circle cx="128.3" cy="52.7" r=".46"/>
<circle cx="135.9" cy="85.1" r=".46"/>
<circle cx="121.9" cy="35.6" r=".46"/>
<circle cx="118.7" cy="35.6" r=".46"/>
<circle cx="135.9" cy="26.7" r=".46"/>
<circle cx="90.8" cy="35.6" r=".46"/>
<circle cx="94.6" cy="35.6" r=".46"/>
<circle cx="87" cy="35.6" r=".46"/>
<circle cx="208.9" cy="41.9" r=".46"/>
<circle cx="179.7" cy="41.9" r=".46"/>
<circle cx="187.3" cy="41.9" r=".46"/>
<circle cx="187.3" cy="55.2" r=".46"/>
<circle cx="179.7" cy="57.8" r=".46"/>
<circle cx="231.8" cy="41.9" r=".46"/>
<circle cx="231.8" cy="67.3" r=".46"/>
<circle cx="61" cy="35.6" r=".46"/>
<circle cx="71.8" cy="44.5" r=".46"/>
<circle cx="71.8" cy="55.2" r=".46"/>
<circle cx="80" cy="57.8" r=".46"/>
</g>
<use href="#words"/>
</svg>
